VERSION 5.7 ;
BUSBITCHARS "[]" ;
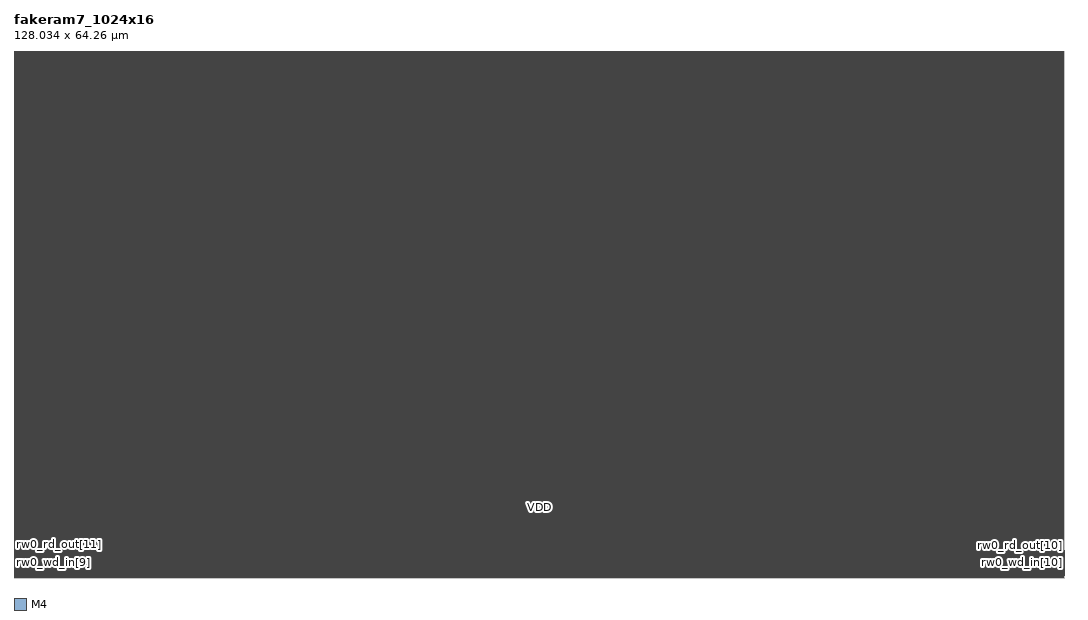
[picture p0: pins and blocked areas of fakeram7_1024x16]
MACRO fakeram7_1024x16
  FOREIGN fakeram7_1024x16 0 0 ;
  SYMMETRY X Y R90 ;
  SIZE 128.034 BY 64.260 ;
  CLASS BLOCK ;
  PIN rw0_clk
    DIRECTION INPUT ;
    USE SIGNAL ;
    SHAPE ABUTMENT ;
    PORT
      LAYER M4 ;
      RECT 0.000 0.276 0.072 0.300 ;
    END
  END rw0_clk
  PIN rw0_ce_in
    DIRECTION INPUT ;
    USE SIGNAL ;
    SHAPE ABUTMENT ;
    PORT
      LAYER M4 ;
      RECT 127.962 0.276 128.034 0.300 ;
    END
  END rw0_ce_in
  PIN rw0_we_in
    DIRECTION INPUT ;
    USE SIGNAL ;
    SHAPE ABUTMENT ;
    PORT
      LAYER M4 ;
      RECT 0.000 0.420 0.072 0.444 ;
    END
  END rw0_we_in
  PIN rw0_addr_in[0]
    DIRECTION INPUT ;
    USE SIGNAL ;
    SHAPE ABUTMENT ;
    PORT
      LAYER M4 ;
      RECT 127.962 0.420 128.034 0.444 ;
    END
  END rw0_addr_in[0]
  PIN rw0_addr_in[1]
    DIRECTION INPUT ;
    USE SIGNAL ;
    SHAPE ABUTMENT ;
    PORT
      LAYER M4 ;
      RECT 0.000 0.564 0.072 0.588 ;
    END
  END rw0_addr_in[1]
  PIN rw0_addr_in[2]
    DIRECTION INPUT ;
    USE SIGNAL ;
    SHAPE ABUTMENT ;
    PORT
      LAYER M4 ;
      RECT 127.962 0.564 128.034 0.588 ;
    END
  END rw0_addr_in[2]
  PIN rw0_addr_in[3]
    DIRECTION INPUT ;
    USE SIGNAL ;
    SHAPE ABUTMENT ;
    PORT
      LAYER M4 ;
      RECT 0.000 0.708 0.072 0.732 ;
    END
  END rw0_addr_in[3]
  PIN rw0_addr_in[4]
    DIRECTION INPUT ;
    USE SIGNAL ;
    SHAPE ABUTMENT ;
    PORT
      LAYER M4 ;
      RECT 127.962 0.708 128.034 0.732 ;
    END
  END rw0_addr_in[4]
  PIN rw0_addr_in[5]
    DIRECTION INPUT ;
    USE SIGNAL ;
    SHAPE ABUTMENT ;
    PORT
      LAYER M4 ;
      RECT 0.000 0.852 0.072 0.876 ;
    END
  END rw0_addr_in[5]
  PIN rw0_addr_in[6]
    DIRECTION INPUT ;
    USE SIGNAL ;
    SHAPE ABUTMENT ;
    PORT
      LAYER M4 ;
      RECT 127.962 0.852 128.034 0.876 ;
    END
  END rw0_addr_in[6]
  PIN rw0_addr_in[7]
    DIRECTION INPUT ;
    USE SIGNAL ;
    SHAPE ABUTMENT ;
    PORT
      LAYER M4 ;
      RECT 0.000 0.996 0.072 1.020 ;
    END
  END rw0_addr_in[7]
  PIN rw0_addr_in[8]
    DIRECTION INPUT ;
    USE SIGNAL ;
    SHAPE ABUTMENT ;
    PORT
      LAYER M4 ;
      RECT 127.962 0.996 128.034 1.020 ;
    END
  END rw0_addr_in[8]
  PIN rw0_addr_in[9]
    DIRECTION INPUT ;
    USE SIGNAL ;
    SHAPE ABUTMENT ;
    PORT
      LAYER M4 ;
      RECT 0.000 1.140 0.072 1.164 ;
    END
  END rw0_addr_in[9]
  PIN rw0_wd_in[0]
    DIRECTION INPUT ;
    USE SIGNAL ;
    SHAPE ABUTMENT ;
    PORT
      LAYER M4 ;
      RECT 127.962 1.140 128.034 1.164 ;
    END
  END rw0_wd_in[0]
  PIN rw0_wd_in[1]
    DIRECTION INPUT ;
    USE SIGNAL ;
    SHAPE ABUTMENT ;
    PORT
      LAYER M4 ;
      RECT 0.000 1.284 0.072 1.308 ;
    END
  END rw0_wd_in[1]
  PIN rw0_wd_in[2]
    DIRECTION INPUT ;
    USE SIGNAL ;
    SHAPE ABUTMENT ;
    PORT
      LAYER M4 ;
      RECT 127.962 1.284 128.034 1.308 ;
    END
  END rw0_wd_in[2]
  PIN rw0_wd_in[3]
    DIRECTION INPUT ;
    USE SIGNAL ;
    SHAPE ABUTMENT ;
    PORT
      LAYER M4 ;
      RECT 0.000 1.428 0.072 1.452 ;
    END
  END rw0_wd_in[3]
  PIN rw0_wd_in[4]
    DIRECTION INPUT ;
    USE SIGNAL ;
    SHAPE ABUTMENT ;
    PORT
      LAYER M4 ;
      RECT 127.962 1.428 128.034 1.452 ;
    END
  END rw0_wd_in[4]
  PIN rw0_wd_in[5]
    DIRECTION INPUT ;
    USE SIGNAL ;
    SHAPE ABUTMENT ;
    PORT
      LAYER M4 ;
      RECT 0.000 1.572 0.072 1.596 ;
    END
  END rw0_wd_in[5]
  PIN rw0_wd_in[6]
    DIRECTION INPUT ;
    USE SIGNAL ;
    SHAPE ABUTMENT ;
    PORT
      LAYER M4 ;
      RECT 127.962 1.572 128.034 1.596 ;
    END
  END rw0_wd_in[6]
  PIN rw0_wd_in[7]
    DIRECTION INPUT ;
    USE SIGNAL ;
    SHAPE ABUTMENT ;
    PORT
      LAYER M4 ;
      RECT 0.000 1.716 0.072 1.740 ;
    END
  END rw0_wd_in[7]
  PIN rw0_wd_in[8]
    DIRECTION INPUT ;
    USE SIGNAL ;
    SHAPE ABUTMENT ;
    PORT
      LAYER M4 ;
      RECT 127.962 1.716 128.034 1.740 ;
    END
  END rw0_wd_in[8]
  PIN rw0_wd_in[9]
    DIRECTION INPUT ;
    USE SIGNAL ;
    SHAPE ABUTMENT ;
    PORT
      LAYER M4 ;
      RECT 0.000 1.860 0.072 1.884 ;
    END
  END rw0_wd_in[9]
  PIN rw0_wd_in[10]
    DIRECTION INPUT ;
    USE SIGNAL ;
    SHAPE ABUTMENT ;
    PORT
      LAYER M4 ;
      RECT 127.962 1.860 128.034 1.884 ;
    END
  END rw0_wd_in[10]
  PIN rw0_wd_in[11]
    DIRECTION INPUT ;
    USE SIGNAL ;
    SHAPE ABUTMENT ;
    PORT
      LAYER M4 ;
      RECT 0.000 2.004 0.072 2.028 ;
    END
  END rw0_wd_in[11]
  PIN rw0_wd_in[12]
    DIRECTION INPUT ;
    USE SIGNAL ;
    SHAPE ABUTMENT ;
    PORT
      LAYER M4 ;
      RECT 127.962 2.004 128.034 2.028 ;
    END
  END rw0_wd_in[12]
  PIN rw0_wd_in[13]
    DIRECTION INPUT ;
    USE SIGNAL ;
    SHAPE ABUTMENT ;
    PORT
      LAYER M4 ;
      RECT 0.000 2.148 0.072 2.172 ;
    END
  END rw0_wd_in[13]
  PIN rw0_wd_in[14]
    DIRECTION INPUT ;
    USE SIGNAL ;
    SHAPE ABUTMENT ;
    PORT
      LAYER M4 ;
      RECT 127.962 2.148 128.034 2.172 ;
    END
  END rw0_wd_in[14]
  PIN rw0_wd_in[15]
    DIRECTION INPUT ;
    USE SIGNAL ;
    SHAPE ABUTMENT ;
    PORT
      LAYER M4 ;
      RECT 0.000 2.292 0.072 2.316 ;
    END
  END rw0_wd_in[15]
  PIN rw0_rd_out[0]
    DIRECTION OUTPUT ;
    USE SIGNAL ;
    SHAPE ABUTMENT ;
    PORT
      LAYER M4 ;
      RECT 127.962 2.292 128.034 2.316 ;
    END
  END rw0_rd_out[0]
  PIN rw0_rd_out[1]
    DIRECTION OUTPUT ;
    USE SIGNAL ;
    SHAPE ABUTMENT ;
    PORT
      LAYER M4 ;
      RECT 0.000 2.436 0.072 2.460 ;
    END
  END rw0_rd_out[1]
  PIN rw0_rd_out[2]
    DIRECTION OUTPUT ;
    USE SIGNAL ;
    SHAPE ABUTMENT ;
    PORT
      LAYER M4 ;
      RECT 127.962 2.436 128.034 2.460 ;
    END
  END rw0_rd_out[2]
  PIN rw0_rd_out[3]
    DIRECTION OUTPUT ;
    USE SIGNAL ;
    SHAPE ABUTMENT ;
    PORT
      LAYER M4 ;
      RECT 0.000 2.580 0.072 2.604 ;
    END
  END rw0_rd_out[3]
  PIN rw0_rd_out[4]
    DIRECTION OUTPUT ;
    USE SIGNAL ;
    SHAPE ABUTMENT ;
    PORT
      LAYER M4 ;
      RECT 127.962 2.580 128.034 2.604 ;
    END
  END rw0_rd_out[4]
  PIN rw0_rd_out[5]
    DIRECTION OUTPUT ;
    USE SIGNAL ;
    SHAPE ABUTMENT ;
    PORT
      LAYER M4 ;
      RECT 0.000 2.724 0.072 2.748 ;
    END
  END rw0_rd_out[5]
  PIN rw0_rd_out[6]
    DIRECTION OUTPUT ;
    USE SIGNAL ;
    SHAPE ABUTMENT ;
    PORT
      LAYER M4 ;
      RECT 127.962 2.724 128.034 2.748 ;
    END
  END rw0_rd_out[6]
  PIN rw0_rd_out[7]
    DIRECTION OUTPUT ;
    USE SIGNAL ;
    SHAPE ABUTMENT ;
    PORT
      LAYER M4 ;
      RECT 0.000 2.868 0.072 2.892 ;
    END
  END rw0_rd_out[7]
  PIN rw0_rd_out[8]
    DIRECTION OUTPUT ;
    USE SIGNAL ;
    SHAPE ABUTMENT ;
    PORT
      LAYER M4 ;
      RECT 127.962 2.868 128.034 2.892 ;
    END
  END rw0_rd_out[8]
  PIN rw0_rd_out[9]
    DIRECTION OUTPUT ;
    USE SIGNAL ;
    SHAPE ABUTMENT ;
    PORT
      LAYER M4 ;
      RECT 0.000 3.012 0.072 3.036 ;
    END
  END rw0_rd_out[9]
  PIN rw0_rd_out[10]
    DIRECTION OUTPUT ;
    USE SIGNAL ;
    SHAPE ABUTMENT ;
    PORT
      LAYER M4 ;
      RECT 127.962 3.012 128.034 3.036 ;
    END
  END rw0_rd_out[10]
  PIN rw0_rd_out[11]
    DIRECTION OUTPUT ;
    USE SIGNAL ;
    SHAPE ABUTMENT ;
    PORT
      LAYER M4 ;
      RECT 0.000 3.156 0.072 3.180 ;
    END
  END rw0_rd_out[11]
  PIN rw0_rd_out[12]
    DIRECTION OUTPUT ;
    USE SIGNAL ;
    SHAPE ABUTMENT ;
    PORT
      LAYER M4 ;
      RECT 127.962 3.156 128.034 3.180 ;
    END
  END rw0_rd_out[12]
  PIN rw0_rd_out[13]
    DIRECTION OUTPUT ;
    USE SIGNAL ;
    SHAPE ABUTMENT ;
    PORT
      LAYER M4 ;
      RECT 0.000 3.300 0.072 3.324 ;
    END
  END rw0_rd_out[13]
  PIN rw0_rd_out[14]
    DIRECTION OUTPUT ;
    USE SIGNAL ;
    SHAPE ABUTMENT ;
    PORT
      LAYER M4 ;
      RECT 127.962 3.300 128.034 3.324 ;
    END
  END rw0_rd_out[14]
  PIN rw0_rd_out[15]
    DIRECTION OUTPUT ;
    USE SIGNAL ;
    SHAPE ABUTMENT ;
    PORT
      LAYER M4 ;
      RECT 0.000 3.444 0.072 3.468 ;
    END
  END rw0_rd_out[15]
  PIN VDD
    DIRECTION INOUT ;
    USE POWER ;
    PORT
      LAYER M4 ;
      RECT 0.054 0.012 127.980 0.036 ;
      RECT 0.054 0.108 127.980 0.132 ;
      RECT 0.054 0.204 127.980 0.228 ;
      RECT 0.054 0.300 127.980 0.324 ;
      RECT 0.054 0.396 127.980 0.420 ;
      RECT 0.054 0.492 127.980 0.516 ;
      RECT 0.054 0.588 127.980 0.612 ;
      RECT 0.054 0.684 127.980 0.708 ;
      RECT 0.054 0.780 127.980 0.804 ;
      RECT 0.054 0.876 127.980 0.900 ;
      RECT 0.054 0.972 127.980 0.996 ;
      RECT 0.054 1.068 127.980 1.092 ;
      RECT 0.054 1.164 127.980 1.188 ;
      RECT 0.054 1.260 127.980 1.284 ;
      RECT 0.054 1.356 127.980 1.380 ;
      RECT 0.054 1.452 127.980 1.476 ;
      RECT 0.054 1.548 127.980 1.572 ;
      RECT 0.054 1.644 127.980 1.668 ;
      RECT 0.054 1.740 127.980 1.764 ;
      RECT 0.054 1.836 127.980 1.860 ;
      RECT 0.054 1.932 127.980 1.956 ;
      RECT 0.054 2.028 127.980 2.052 ;
      RECT 0.054 2.124 127.980 2.148 ;
      RECT 0.054 2.220 127.980 2.244 ;
      RECT 0.054 2.316 127.980 2.340 ;
      RECT 0.054 2.412 127.980 2.436 ;
      RECT 0.054 2.508 127.980 2.532 ;
      RECT 0.054 2.604 127.980 2.628 ;
      RECT 0.054 2.700 127.980 2.724 ;
      RECT 0.054 2.796 127.980 2.820 ;
      RECT 0.054 2.892 127.980 2.916 ;
      RECT 0.054 2.988 127.980 3.012 ;
      RECT 0.054 3.084 127.980 3.108 ;
      RECT 0.054 3.180 127.980 3.204 ;
      RECT 0.054 3.276 127.980 3.300 ;
      RECT 0.054 3.372 127.980 3.396 ;
      RECT 0.054 3.468 127.980 3.492 ;
      RECT 0.054 3.564 127.980 3.588 ;
      RECT 0.054 3.660 127.980 3.684 ;
      RECT 0.054 3.756 127.980 3.780 ;
      RECT 0.054 3.852 127.980 3.876 ;
      RECT 0.054 3.948 127.980 3.972 ;
      RECT 0.054 4.044 127.980 4.068 ;
      RECT 0.054 4.140 127.980 4.164 ;
      RECT 0.054 4.236 127.980 4.260 ;
      RECT 0.054 4.332 127.980 4.356 ;
      RECT 0.054 4.428 127.980 4.452 ;
      RECT 0.054 4.524 127.980 4.548 ;
      RECT 0.054 4.620 127.980 4.644 ;
      RECT 0.054 4.716 127.980 4.740 ;
      RECT 0.054 4.812 127.980 4.836 ;
      RECT 0.054 4.908 127.980 4.932 ;
      RECT 0.054 5.004 127.980 5.028 ;
      RECT 0.054 5.100 127.980 5.124 ;
      RECT 0.054 5.196 127.980 5.220 ;
      RECT 0.054 5.292 127.980 5.316 ;
      RECT 0.054 5.388 127.980 5.412 ;
      RECT 0.054 5.484 127.980 5.508 ;
      RECT 0.054 5.580 127.980 5.604 ;
      RECT 0.054 5.676 127.980 5.700 ;
      RECT 0.054 5.772 127.980 5.796 ;
      RECT 0.054 5.868 127.980 5.892 ;
      RECT 0.054 5.964 127.980 5.988 ;
      RECT 0.054 6.060 127.980 6.084 ;
      RECT 0.054 6.156 127.980 6.180 ;
      RECT 0.054 6.252 127.980 6.276 ;
      RECT 0.054 6.348 127.980 6.372 ;
      RECT 0.054 6.444 127.980 6.468 ;
      RECT 0.054 6.540 127.980 6.564 ;
      RECT 0.054 6.636 127.980 6.660 ;
      RECT 0.054 6.732 127.980 6.756 ;
      RECT 0.054 6.828 127.980 6.852 ;
      RECT 0.054 6.924 127.980 6.948 ;
      RECT 0.054 7.020 127.980 7.044 ;
      RECT 0.054 7.116 127.980 7.140 ;
      RECT 0.054 7.212 127.980 7.236 ;
      RECT 0.054 7.308 127.980 7.332 ;
      RECT 0.054 7.404 127.980 7.428 ;
      RECT 0.054 7.500 127.980 7.524 ;
      RECT 0.054 7.596 127.980 7.620 ;
      RECT 0.054 7.692 127.980 7.716 ;
      RECT 0.054 7.788 127.980 7.812 ;
      RECT 0.054 7.884 127.980 7.908 ;
      RECT 0.054 7.980 127.980 8.004 ;
      RECT 0.054 8.076 127.980 8.100 ;
      RECT 0.054 8.172 127.980 8.196 ;
      RECT 0.054 8.268 127.980 8.292 ;
      RECT 0.054 8.364 127.980 8.388 ;
      RECT 0.054 8.460 127.980 8.484 ;
      RECT 0.054 8.556 127.980 8.580 ;
      RECT 0.054 8.652 127.980 8.676 ;
      RECT 0.054 8.748 127.980 8.772 ;
      RECT 0.054 8.844 127.980 8.868 ;
      RECT 0.054 8.940 127.980 8.964 ;
      RECT 0.054 9.036 127.980 9.060 ;
      RECT 0.054 9.132 127.980 9.156 ;
      RECT 0.054 9.228 127.980 9.252 ;
      RECT 0.054 9.324 127.980 9.348 ;
      RECT 0.054 9.420 127.980 9.444 ;
      RECT 0.054 9.516 127.980 9.540 ;
      RECT 0.054 9.612 127.980 9.636 ;
      RECT 0.054 9.708 127.980 9.732 ;
      RECT 0.054 9.804 127.980 9.828 ;
      RECT 0.054 9.900 127.980 9.924 ;
      RECT 0.054 9.996 127.980 10.020 ;
      RECT 0.054 10.092 127.980 10.116 ;
      RECT 0.054 10.188 127.980 10.212 ;
      RECT 0.054 10.284 127.980 10.308 ;
      RECT 0.054 10.380 127.980 10.404 ;
      RECT 0.054 10.476 127.980 10.500 ;
      RECT 0.054 10.572 127.980 10.596 ;
      RECT 0.054 10.668 127.980 10.692 ;
      RECT 0.054 10.764 127.980 10.788 ;
      RECT 0.054 10.860 127.980 10.884 ;
      RECT 0.054 10.956 127.980 10.980 ;
      RECT 0.054 11.052 127.980 11.076 ;
      RECT 0.054 11.148 127.980 11.172 ;
      RECT 0.054 11.244 127.980 11.268 ;
      RECT 0.054 11.340 127.980 11.364 ;
      RECT 0.054 11.436 127.980 11.460 ;
      RECT 0.054 11.532 127.980 11.556 ;
      RECT 0.054 11.628 127.980 11.652 ;
      RECT 0.054 11.724 127.980 11.748 ;
      RECT 0.054 11.820 127.980 11.844 ;
      RECT 0.054 11.916 127.980 11.940 ;
      RECT 0.054 12.012 127.980 12.036 ;
      RECT 0.054 12.108 127.980 12.132 ;
      RECT 0.054 12.204 127.980 12.228 ;
      RECT 0.054 12.300 127.980 12.324 ;
      RECT 0.054 12.396 127.980 12.420 ;
      RECT 0.054 12.492 127.980 12.516 ;
      RECT 0.054 12.588 127.980 12.612 ;
      RECT 0.054 12.684 127.980 12.708 ;
      RECT 0.054 12.780 127.980 12.804 ;
      RECT 0.054 12.876 127.980 12.900 ;
      RECT 0.054 12.972 127.980 12.996 ;
      RECT 0.054 13.068 127.980 13.092 ;
      RECT 0.054 13.164 127.980 13.188 ;
      RECT 0.054 13.260 127.980 13.284 ;
      RECT 0.054 13.356 127.980 13.380 ;
      RECT 0.054 13.452 127.980 13.476 ;
      RECT 0.054 13.548 127.980 13.572 ;
      RECT 0.054 13.644 127.980 13.668 ;
      RECT 0.054 13.740 127.980 13.764 ;
      RECT 0.054 13.836 127.980 13.860 ;
      RECT 0.054 13.932 127.980 13.956 ;
      RECT 0.054 14.028 127.980 14.052 ;
      RECT 0.054 14.124 127.980 14.148 ;
      RECT 0.054 14.220 127.980 14.244 ;
      RECT 0.054 14.316 127.980 14.340 ;
      RECT 0.054 14.412 127.980 14.436 ;
      RECT 0.054 14.508 127.980 14.532 ;
      RECT 0.054 14.604 127.980 14.628 ;
      RECT 0.054 14.700 127.980 14.724 ;
      RECT 0.054 14.796 127.980 14.820 ;
      RECT 0.054 14.892 127.980 14.916 ;
      RECT 0.054 14.988 127.980 15.012 ;
      RECT 0.054 15.084 127.980 15.108 ;
      RECT 0.054 15.180 127.980 15.204 ;
      RECT 0.054 15.276 127.980 15.300 ;
      RECT 0.054 15.372 127.980 15.396 ;
      RECT 0.054 15.468 127.980 15.492 ;
      RECT 0.054 15.564 127.980 15.588 ;
      RECT 0.054 15.660 127.980 15.684 ;
      RECT 0.054 15.756 127.980 15.780 ;
      RECT 0.054 15.852 127.980 15.876 ;
      RECT 0.054 15.948 127.980 15.972 ;
      RECT 0.054 16.044 127.980 16.068 ;
      RECT 0.054 16.140 127.980 16.164 ;
      RECT 0.054 16.236 127.980 16.260 ;
      RECT 0.054 16.332 127.980 16.356 ;
      RECT 0.054 16.428 127.980 16.452 ;
      RECT 0.054 16.524 127.980 16.548 ;
      RECT 0.054 16.620 127.980 16.644 ;
      RECT 0.054 16.716 127.980 16.740 ;
      RECT 0.054 16.812 127.980 16.836 ;
      RECT 0.054 16.908 127.980 16.932 ;
      RECT 0.054 17.004 127.980 17.028 ;
      RECT 0.054 17.100 127.980 17.124 ;
      RECT 0.054 17.196 127.980 17.220 ;
      RECT 0.054 17.292 127.980 17.316 ;
      RECT 0.054 17.388 127.980 17.412 ;
      RECT 0.054 17.484 127.980 17.508 ;
      RECT 0.054 17.580 127.980 17.604 ;
      RECT 0.054 17.676 127.980 17.700 ;
      RECT 0.054 17.772 127.980 17.796 ;
      RECT 0.054 17.868 127.980 17.892 ;
      RECT 0.054 17.964 127.980 17.988 ;
      RECT 0.054 18.060 127.980 18.084 ;
      RECT 0.054 18.156 127.980 18.180 ;
      RECT 0.054 18.252 127.980 18.276 ;
      RECT 0.054 18.348 127.980 18.372 ;
      RECT 0.054 18.444 127.980 18.468 ;
      RECT 0.054 18.540 127.980 18.564 ;
      RECT 0.054 18.636 127.980 18.660 ;
      RECT 0.054 18.732 127.980 18.756 ;
      RECT 0.054 18.828 127.980 18.852 ;
      RECT 0.054 18.924 127.980 18.948 ;
      RECT 0.054 19.020 127.980 19.044 ;
      RECT 0.054 19.116 127.980 19.140 ;
      RECT 0.054 19.212 127.980 19.236 ;
      RECT 0.054 19.308 127.980 19.332 ;
      RECT 0.054 19.404 127.980 19.428 ;
      RECT 0.054 19.500 127.980 19.524 ;
      RECT 0.054 19.596 127.980 19.620 ;
      RECT 0.054 19.692 127.980 19.716 ;
      RECT 0.054 19.788 127.980 19.812 ;
      RECT 0.054 19.884 127.980 19.908 ;
      RECT 0.054 19.980 127.980 20.004 ;
      RECT 0.054 20.076 127.980 20.100 ;
      RECT 0.054 20.172 127.980 20.196 ;
      RECT 0.054 20.268 127.980 20.292 ;
      RECT 0.054 20.364 127.980 20.388 ;
      RECT 0.054 20.460 127.980 20.484 ;
      RECT 0.054 20.556 127.980 20.580 ;
      RECT 0.054 20.652 127.980 20.676 ;
      RECT 0.054 20.748 127.980 20.772 ;
      RECT 0.054 20.844 127.980 20.868 ;
      RECT 0.054 20.940 127.980 20.964 ;
      RECT 0.054 21.036 127.980 21.060 ;
      RECT 0.054 21.132 127.980 21.156 ;
      RECT 0.054 21.228 127.980 21.252 ;
      RECT 0.054 21.324 127.980 21.348 ;
      RECT 0.054 21.420 127.980 21.444 ;
      RECT 0.054 21.516 127.980 21.540 ;
      RECT 0.054 21.612 127.980 21.636 ;
      RECT 0.054 21.708 127.980 21.732 ;
      RECT 0.054 21.804 127.980 21.828 ;
      RECT 0.054 21.900 127.980 21.924 ;
      RECT 0.054 21.996 127.980 22.020 ;
      RECT 0.054 22.092 127.980 22.116 ;
      RECT 0.054 22.188 127.980 22.212 ;
      RECT 0.054 22.284 127.980 22.308 ;
      RECT 0.054 22.380 127.980 22.404 ;
      RECT 0.054 22.476 127.980 22.500 ;
      RECT 0.054 22.572 127.980 22.596 ;
      RECT 0.054 22.668 127.980 22.692 ;
      RECT 0.054 22.764 127.980 22.788 ;
      RECT 0.054 22.860 127.980 22.884 ;
      RECT 0.054 22.956 127.980 22.980 ;
      RECT 0.054 23.052 127.980 23.076 ;
      RECT 0.054 23.148 127.980 23.172 ;
      RECT 0.054 23.244 127.980 23.268 ;
      RECT 0.054 23.340 127.980 23.364 ;
      RECT 0.054 23.436 127.980 23.460 ;
      RECT 0.054 23.532 127.980 23.556 ;
      RECT 0.054 23.628 127.980 23.652 ;
      RECT 0.054 23.724 127.980 23.748 ;
      RECT 0.054 23.820 127.980 23.844 ;
      RECT 0.054 23.916 127.980 23.940 ;
      RECT 0.054 24.012 127.980 24.036 ;
      RECT 0.054 24.108 127.980 24.132 ;
      RECT 0.054 24.204 127.980 24.228 ;
      RECT 0.054 24.300 127.980 24.324 ;
      RECT 0.054 24.396 127.980 24.420 ;
      RECT 0.054 24.492 127.980 24.516 ;
      RECT 0.054 24.588 127.980 24.612 ;
      RECT 0.054 24.684 127.980 24.708 ;
      RECT 0.054 24.780 127.980 24.804 ;
      RECT 0.054 24.876 127.980 24.900 ;
      RECT 0.054 24.972 127.980 24.996 ;
      RECT 0.054 25.068 127.980 25.092 ;
      RECT 0.054 25.164 127.980 25.188 ;
      RECT 0.054 25.260 127.980 25.284 ;
      RECT 0.054 25.356 127.980 25.380 ;
      RECT 0.054 25.452 127.980 25.476 ;
      RECT 0.054 25.548 127.980 25.572 ;
      RECT 0.054 25.644 127.980 25.668 ;
      RECT 0.054 25.740 127.980 25.764 ;
      RECT 0.054 25.836 127.980 25.860 ;
      RECT 0.054 25.932 127.980 25.956 ;
      RECT 0.054 26.028 127.980 26.052 ;
      RECT 0.054 26.124 127.980 26.148 ;
      RECT 0.054 26.220 127.980 26.244 ;
      RECT 0.054 26.316 127.980 26.340 ;
      RECT 0.054 26.412 127.980 26.436 ;
      RECT 0.054 26.508 127.980 26.532 ;
      RECT 0.054 26.604 127.980 26.628 ;
      RECT 0.054 26.700 127.980 26.724 ;
      RECT 0.054 26.796 127.980 26.820 ;
      RECT 0.054 26.892 127.980 26.916 ;
      RECT 0.054 26.988 127.980 27.012 ;
      RECT 0.054 27.084 127.980 27.108 ;
      RECT 0.054 27.180 127.980 27.204 ;
      RECT 0.054 27.276 127.980 27.300 ;
      RECT 0.054 27.372 127.980 27.396 ;
      RECT 0.054 27.468 127.980 27.492 ;
      RECT 0.054 27.564 127.980 27.588 ;
      RECT 0.054 27.660 127.980 27.684 ;
      RECT 0.054 27.756 127.980 27.780 ;
      RECT 0.054 27.852 127.980 27.876 ;
      RECT 0.054 27.948 127.980 27.972 ;
      RECT 0.054 28.044 127.980 28.068 ;
      RECT 0.054 28.140 127.980 28.164 ;
      RECT 0.054 28.236 127.980 28.260 ;
      RECT 0.054 28.332 127.980 28.356 ;
      RECT 0.054 28.428 127.980 28.452 ;
      RECT 0.054 28.524 127.980 28.548 ;
      RECT 0.054 28.620 127.980 28.644 ;
      RECT 0.054 28.716 127.980 28.740 ;
      RECT 0.054 28.812 127.980 28.836 ;
      RECT 0.054 28.908 127.980 28.932 ;
      RECT 0.054 29.004 127.980 29.028 ;
      RECT 0.054 29.100 127.980 29.124 ;
      RECT 0.054 29.196 127.980 29.220 ;
      RECT 0.054 29.292 127.980 29.316 ;
      RECT 0.054 29.388 127.980 29.412 ;
      RECT 0.054 29.484 127.980 29.508 ;
      RECT 0.054 29.580 127.980 29.604 ;
      RECT 0.054 29.676 127.980 29.700 ;
      RECT 0.054 29.772 127.980 29.796 ;
      RECT 0.054 29.868 127.980 29.892 ;
      RECT 0.054 29.964 127.980 29.988 ;
      RECT 0.054 30.060 127.980 30.084 ;
      RECT 0.054 30.156 127.980 30.180 ;
      RECT 0.054 30.252 127.980 30.276 ;
      RECT 0.054 30.348 127.980 30.372 ;
      RECT 0.054 30.444 127.980 30.468 ;
      RECT 0.054 30.540 127.980 30.564 ;
      RECT 0.054 30.636 127.980 30.660 ;
      RECT 0.054 30.732 127.980 30.756 ;
      RECT 0.054 30.828 127.980 30.852 ;
      RECT 0.054 30.924 127.980 30.948 ;
      RECT 0.054 31.020 127.980 31.044 ;
      RECT 0.054 31.116 127.980 31.140 ;
      RECT 0.054 31.212 127.980 31.236 ;
      RECT 0.054 31.308 127.980 31.332 ;
      RECT 0.054 31.404 127.980 31.428 ;
      RECT 0.054 31.500 127.980 31.524 ;
      RECT 0.054 31.596 127.980 31.620 ;
      RECT 0.054 31.692 127.980 31.716 ;
      RECT 0.054 31.788 127.980 31.812 ;
      RECT 0.054 31.884 127.980 31.908 ;
      RECT 0.054 31.980 127.980 32.004 ;
      RECT 0.054 32.076 127.980 32.100 ;
      RECT 0.054 32.172 127.980 32.196 ;
      RECT 0.054 32.268 127.980 32.292 ;
      RECT 0.054 32.364 127.980 32.388 ;
      RECT 0.054 32.460 127.980 32.484 ;
      RECT 0.054 32.556 127.980 32.580 ;
      RECT 0.054 32.652 127.980 32.676 ;
      RECT 0.054 32.748 127.980 32.772 ;
      RECT 0.054 32.844 127.980 32.868 ;
      RECT 0.054 32.940 127.980 32.964 ;
      RECT 0.054 33.036 127.980 33.060 ;
      RECT 0.054 33.132 127.980 33.156 ;
      RECT 0.054 33.228 127.980 33.252 ;
      RECT 0.054 33.324 127.980 33.348 ;
      RECT 0.054 33.420 127.980 33.444 ;
      RECT 0.054 33.516 127.980 33.540 ;
      RECT 0.054 33.612 127.980 33.636 ;
      RECT 0.054 33.708 127.980 33.732 ;
      RECT 0.054 33.804 127.980 33.828 ;
      RECT 0.054 33.900 127.980 33.924 ;
      RECT 0.054 33.996 127.980 34.020 ;
      RECT 0.054 34.092 127.980 34.116 ;
      RECT 0.054 34.188 127.980 34.212 ;
      RECT 0.054 34.284 127.980 34.308 ;
      RECT 0.054 34.380 127.980 34.404 ;
      RECT 0.054 34.476 127.980 34.500 ;
      RECT 0.054 34.572 127.980 34.596 ;
      RECT 0.054 34.668 127.980 34.692 ;
      RECT 0.054 34.764 127.980 34.788 ;
      RECT 0.054 34.860 127.980 34.884 ;
      RECT 0.054 34.956 127.980 34.980 ;
      RECT 0.054 35.052 127.980 35.076 ;
      RECT 0.054 35.148 127.980 35.172 ;
      RECT 0.054 35.244 127.980 35.268 ;
      RECT 0.054 35.340 127.980 35.364 ;
      RECT 0.054 35.436 127.980 35.460 ;
      RECT 0.054 35.532 127.980 35.556 ;
      RECT 0.054 35.628 127.980 35.652 ;
      RECT 0.054 35.724 127.980 35.748 ;
      RECT 0.054 35.820 127.980 35.844 ;
      RECT 0.054 35.916 127.980 35.940 ;
      RECT 0.054 36.012 127.980 36.036 ;
      RECT 0.054 36.108 127.980 36.132 ;
      RECT 0.054 36.204 127.980 36.228 ;
      RECT 0.054 36.300 127.980 36.324 ;
      RECT 0.054 36.396 127.980 36.420 ;
      RECT 0.054 36.492 127.980 36.516 ;
      RECT 0.054 36.588 127.980 36.612 ;
      RECT 0.054 36.684 127.980 36.708 ;
      RECT 0.054 36.780 127.980 36.804 ;
      RECT 0.054 36.876 127.980 36.900 ;
      RECT 0.054 36.972 127.980 36.996 ;
      RECT 0.054 37.068 127.980 37.092 ;
      RECT 0.054 37.164 127.980 37.188 ;
      RECT 0.054 37.260 127.980 37.284 ;
      RECT 0.054 37.356 127.980 37.380 ;
      RECT 0.054 37.452 127.980 37.476 ;
      RECT 0.054 37.548 127.980 37.572 ;
      RECT 0.054 37.644 127.980 37.668 ;
      RECT 0.054 37.740 127.980 37.764 ;
      RECT 0.054 37.836 127.980 37.860 ;
      RECT 0.054 37.932 127.980 37.956 ;
      RECT 0.054 38.028 127.980 38.052 ;
      RECT 0.054 38.124 127.980 38.148 ;
      RECT 0.054 38.220 127.980 38.244 ;
      RECT 0.054 38.316 127.980 38.340 ;
      RECT 0.054 38.412 127.980 38.436 ;
      RECT 0.054 38.508 127.980 38.532 ;
      RECT 0.054 38.604 127.980 38.628 ;
      RECT 0.054 38.700 127.980 38.724 ;
      RECT 0.054 38.796 127.980 38.820 ;
      RECT 0.054 38.892 127.980 38.916 ;
      RECT 0.054 38.988 127.980 39.012 ;
      RECT 0.054 39.084 127.980 39.108 ;
      RECT 0.054 39.180 127.980 39.204 ;
      RECT 0.054 39.276 127.980 39.300 ;
      RECT 0.054 39.372 127.980 39.396 ;
      RECT 0.054 39.468 127.980 39.492 ;
      RECT 0.054 39.564 127.980 39.588 ;
      RECT 0.054 39.660 127.980 39.684 ;
      RECT 0.054 39.756 127.980 39.780 ;
      RECT 0.054 39.852 127.980 39.876 ;
      RECT 0.054 39.948 127.980 39.972 ;
      RECT 0.054 40.044 127.980 40.068 ;
      RECT 0.054 40.140 127.980 40.164 ;
      RECT 0.054 40.236 127.980 40.260 ;
      RECT 0.054 40.332 127.980 40.356 ;
      RECT 0.054 40.428 127.980 40.452 ;
      RECT 0.054 40.524 127.980 40.548 ;
      RECT 0.054 40.620 127.980 40.644 ;
      RECT 0.054 40.716 127.980 40.740 ;
      RECT 0.054 40.812 127.980 40.836 ;
      RECT 0.054 40.908 127.980 40.932 ;
      RECT 0.054 41.004 127.980 41.028 ;
      RECT 0.054 41.100 127.980 41.124 ;
      RECT 0.054 41.196 127.980 41.220 ;
      RECT 0.054 41.292 127.980 41.316 ;
      RECT 0.054 41.388 127.980 41.412 ;
      RECT 0.054 41.484 127.980 41.508 ;
      RECT 0.054 41.580 127.980 41.604 ;
      RECT 0.054 41.676 127.980 41.700 ;
      RECT 0.054 41.772 127.980 41.796 ;
      RECT 0.054 41.868 127.980 41.892 ;
      RECT 0.054 41.964 127.980 41.988 ;
      RECT 0.054 42.060 127.980 42.084 ;
      RECT 0.054 42.156 127.980 42.180 ;
      RECT 0.054 42.252 127.980 42.276 ;
      RECT 0.054 42.348 127.980 42.372 ;
      RECT 0.054 42.444 127.980 42.468 ;
      RECT 0.054 42.540 127.980 42.564 ;
      RECT 0.054 42.636 127.980 42.660 ;
      RECT 0.054 42.732 127.980 42.756 ;
      RECT 0.054 42.828 127.980 42.852 ;
      RECT 0.054 42.924 127.980 42.948 ;
      RECT 0.054 43.020 127.980 43.044 ;
      RECT 0.054 43.116 127.980 43.140 ;
      RECT 0.054 43.212 127.980 43.236 ;
      RECT 0.054 43.308 127.980 43.332 ;
      RECT 0.054 43.404 127.980 43.428 ;
      RECT 0.054 43.500 127.980 43.524 ;
      RECT 0.054 43.596 127.980 43.620 ;
      RECT 0.054 43.692 127.980 43.716 ;
      RECT 0.054 43.788 127.980 43.812 ;
      RECT 0.054 43.884 127.980 43.908 ;
      RECT 0.054 43.980 127.980 44.004 ;
      RECT 0.054 44.076 127.980 44.100 ;
      RECT 0.054 44.172 127.980 44.196 ;
      RECT 0.054 44.268 127.980 44.292 ;
      RECT 0.054 44.364 127.980 44.388 ;
      RECT 0.054 44.460 127.980 44.484 ;
      RECT 0.054 44.556 127.980 44.580 ;
      RECT 0.054 44.652 127.980 44.676 ;
      RECT 0.054 44.748 127.980 44.772 ;
      RECT 0.054 44.844 127.980 44.868 ;
      RECT 0.054 44.940 127.980 44.964 ;
      RECT 0.054 45.036 127.980 45.060 ;
      RECT 0.054 45.132 127.980 45.156 ;
      RECT 0.054 45.228 127.980 45.252 ;
      RECT 0.054 45.324 127.980 45.348 ;
      RECT 0.054 45.420 127.980 45.444 ;
      RECT 0.054 45.516 127.980 45.540 ;
      RECT 0.054 45.612 127.980 45.636 ;
      RECT 0.054 45.708 127.980 45.732 ;
      RECT 0.054 45.804 127.980 45.828 ;
      RECT 0.054 45.900 127.980 45.924 ;
      RECT 0.054 45.996 127.980 46.020 ;
      RECT 0.054 46.092 127.980 46.116 ;
      RECT 0.054 46.188 127.980 46.212 ;
      RECT 0.054 46.284 127.980 46.308 ;
      RECT 0.054 46.380 127.980 46.404 ;
      RECT 0.054 46.476 127.980 46.500 ;
      RECT 0.054 46.572 127.980 46.596 ;
      RECT 0.054 46.668 127.980 46.692 ;
      RECT 0.054 46.764 127.980 46.788 ;
      RECT 0.054 46.860 127.980 46.884 ;
      RECT 0.054 46.956 127.980 46.980 ;
      RECT 0.054 47.052 127.980 47.076 ;
      RECT 0.054 47.148 127.980 47.172 ;
      RECT 0.054 47.244 127.980 47.268 ;
      RECT 0.054 47.340 127.980 47.364 ;
      RECT 0.054 47.436 127.980 47.460 ;
      RECT 0.054 47.532 127.980 47.556 ;
      RECT 0.054 47.628 127.980 47.652 ;
      RECT 0.054 47.724 127.980 47.748 ;
      RECT 0.054 47.820 127.980 47.844 ;
      RECT 0.054 47.916 127.980 47.940 ;
      RECT 0.054 48.012 127.980 48.036 ;
      RECT 0.054 48.108 127.980 48.132 ;
      RECT 0.054 48.204 127.980 48.228 ;
      RECT 0.054 48.300 127.980 48.324 ;
      RECT 0.054 48.396 127.980 48.420 ;
      RECT 0.054 48.492 127.980 48.516 ;
      RECT 0.054 48.588 127.980 48.612 ;
      RECT 0.054 48.684 127.980 48.708 ;
      RECT 0.054 48.780 127.980 48.804 ;
      RECT 0.054 48.876 127.980 48.900 ;
      RECT 0.054 48.972 127.980 48.996 ;
      RECT 0.054 49.068 127.980 49.092 ;
      RECT 0.054 49.164 127.980 49.188 ;
      RECT 0.054 49.260 127.980 49.284 ;
      RECT 0.054 49.356 127.980 49.380 ;
      RECT 0.054 49.452 127.980 49.476 ;
      RECT 0.054 49.548 127.980 49.572 ;
      RECT 0.054 49.644 127.980 49.668 ;
      RECT 0.054 49.740 127.980 49.764 ;
      RECT 0.054 49.836 127.980 49.860 ;
      RECT 0.054 49.932 127.980 49.956 ;
      RECT 0.054 50.028 127.980 50.052 ;
      RECT 0.054 50.124 127.980 50.148 ;
      RECT 0.054 50.220 127.980 50.244 ;
      RECT 0.054 50.316 127.980 50.340 ;
      RECT 0.054 50.412 127.980 50.436 ;
      RECT 0.054 50.508 127.980 50.532 ;
      RECT 0.054 50.604 127.980 50.628 ;
      RECT 0.054 50.700 127.980 50.724 ;
      RECT 0.054 50.796 127.980 50.820 ;
      RECT 0.054 50.892 127.980 50.916 ;
      RECT 0.054 50.988 127.980 51.012 ;
      RECT 0.054 51.084 127.980 51.108 ;
      RECT 0.054 51.180 127.980 51.204 ;
      RECT 0.054 51.276 127.980 51.300 ;
      RECT 0.054 51.372 127.980 51.396 ;
      RECT 0.054 51.468 127.980 51.492 ;
      RECT 0.054 51.564 127.980 51.588 ;
      RECT 0.054 51.660 127.980 51.684 ;
      RECT 0.054 51.756 127.980 51.780 ;
      RECT 0.054 51.852 127.980 51.876 ;
      RECT 0.054 51.948 127.980 51.972 ;
      RECT 0.054 52.044 127.980 52.068 ;
      RECT 0.054 52.140 127.980 52.164 ;
      RECT 0.054 52.236 127.980 52.260 ;
      RECT 0.054 52.332 127.980 52.356 ;
      RECT 0.054 52.428 127.980 52.452 ;
      RECT 0.054 52.524 127.980 52.548 ;
      RECT 0.054 52.620 127.980 52.644 ;
      RECT 0.054 52.716 127.980 52.740 ;
      RECT 0.054 52.812 127.980 52.836 ;
      RECT 0.054 52.908 127.980 52.932 ;
      RECT 0.054 53.004 127.980 53.028 ;
      RECT 0.054 53.100 127.980 53.124 ;
      RECT 0.054 53.196 127.980 53.220 ;
      RECT 0.054 53.292 127.980 53.316 ;
      RECT 0.054 53.388 127.980 53.412 ;
      RECT 0.054 53.484 127.980 53.508 ;
      RECT 0.054 53.580 127.980 53.604 ;
      RECT 0.054 53.676 127.980 53.700 ;
      RECT 0.054 53.772 127.980 53.796 ;
      RECT 0.054 53.868 127.980 53.892 ;
      RECT 0.054 53.964 127.980 53.988 ;
      RECT 0.054 54.060 127.980 54.084 ;
      RECT 0.054 54.156 127.980 54.180 ;
      RECT 0.054 54.252 127.980 54.276 ;
      RECT 0.054 54.348 127.980 54.372 ;
      RECT 0.054 54.444 127.980 54.468 ;
      RECT 0.054 54.540 127.980 54.564 ;
      RECT 0.054 54.636 127.980 54.660 ;
      RECT 0.054 54.732 127.980 54.756 ;
      RECT 0.054 54.828 127.980 54.852 ;
      RECT 0.054 54.924 127.980 54.948 ;
      RECT 0.054 55.020 127.980 55.044 ;
      RECT 0.054 55.116 127.980 55.140 ;
      RECT 0.054 55.212 127.980 55.236 ;
      RECT 0.054 55.308 127.980 55.332 ;
      RECT 0.054 55.404 127.980 55.428 ;
      RECT 0.054 55.500 127.980 55.524 ;
      RECT 0.054 55.596 127.980 55.620 ;
      RECT 0.054 55.692 127.980 55.716 ;
      RECT 0.054 55.788 127.980 55.812 ;
      RECT 0.054 55.884 127.980 55.908 ;
      RECT 0.054 55.980 127.980 56.004 ;
      RECT 0.054 56.076 127.980 56.100 ;
      RECT 0.054 56.172 127.980 56.196 ;
      RECT 0.054 56.268 127.980 56.292 ;
      RECT 0.054 56.364 127.980 56.388 ;
      RECT 0.054 56.460 127.980 56.484 ;
      RECT 0.054 56.556 127.980 56.580 ;
      RECT 0.054 56.652 127.980 56.676 ;
      RECT 0.054 56.748 127.980 56.772 ;
      RECT 0.054 56.844 127.980 56.868 ;
      RECT 0.054 56.940 127.980 56.964 ;
      RECT 0.054 57.036 127.980 57.060 ;
      RECT 0.054 57.132 127.980 57.156 ;
      RECT 0.054 57.228 127.980 57.252 ;
      RECT 0.054 57.324 127.980 57.348 ;
      RECT 0.054 57.420 127.980 57.444 ;
      RECT 0.054 57.516 127.980 57.540 ;
      RECT 0.054 57.612 127.980 57.636 ;
      RECT 0.054 57.708 127.980 57.732 ;
      RECT 0.054 57.804 127.980 57.828 ;
      RECT 0.054 57.900 127.980 57.924 ;
      RECT 0.054 57.996 127.980 58.020 ;
      RECT 0.054 58.092 127.980 58.116 ;
      RECT 0.054 58.188 127.980 58.212 ;
      RECT 0.054 58.284 127.980 58.308 ;
      RECT 0.054 58.380 127.980 58.404 ;
      RECT 0.054 58.476 127.980 58.500 ;
      RECT 0.054 58.572 127.980 58.596 ;
      RECT 0.054 58.668 127.980 58.692 ;
      RECT 0.054 58.764 127.980 58.788 ;
      RECT 0.054 58.860 127.980 58.884 ;
      RECT 0.054 58.956 127.980 58.980 ;
      RECT 0.054 59.052 127.980 59.076 ;
      RECT 0.054 59.148 127.980 59.172 ;
      RECT 0.054 59.244 127.980 59.268 ;
      RECT 0.054 59.340 127.980 59.364 ;
      RECT 0.054 59.436 127.980 59.460 ;
      RECT 0.054 59.532 127.980 59.556 ;
      RECT 0.054 59.628 127.980 59.652 ;
      RECT 0.054 59.724 127.980 59.748 ;
      RECT 0.054 59.820 127.980 59.844 ;
      RECT 0.054 59.916 127.980 59.940 ;
      RECT 0.054 60.012 127.980 60.036 ;
      RECT 0.054 60.108 127.980 60.132 ;
      RECT 0.054 60.204 127.980 60.228 ;
      RECT 0.054 60.300 127.980 60.324 ;
      RECT 0.054 60.396 127.980 60.420 ;
      RECT 0.054 60.492 127.980 60.516 ;
      RECT 0.054 60.588 127.980 60.612 ;
      RECT 0.054 60.684 127.980 60.708 ;
      RECT 0.054 60.780 127.980 60.804 ;
      RECT 0.054 60.876 127.980 60.900 ;
      RECT 0.054 60.972 127.980 60.996 ;
      RECT 0.054 61.068 127.980 61.092 ;
      RECT 0.054 61.164 127.980 61.188 ;
      RECT 0.054 61.260 127.980 61.284 ;
      RECT 0.054 61.356 127.980 61.380 ;
      RECT 0.054 61.452 127.980 61.476 ;
      RECT 0.054 61.548 127.980 61.572 ;
      RECT 0.054 61.644 127.980 61.668 ;
      RECT 0.054 61.740 127.980 61.764 ;
      RECT 0.054 61.836 127.980 61.860 ;
      RECT 0.054 61.932 127.980 61.956 ;
      RECT 0.054 62.028 127.980 62.052 ;
      RECT 0.054 62.124 127.980 62.148 ;
      RECT 0.054 62.220 127.980 62.244 ;
      RECT 0.054 62.316 127.980 62.340 ;
      RECT 0.054 62.412 127.980 62.436 ;
      RECT 0.054 62.508 127.980 62.532 ;
      RECT 0.054 62.604 127.980 62.628 ;
      RECT 0.054 62.700 127.980 62.724 ;
      RECT 0.054 62.796 127.980 62.820 ;
      RECT 0.054 62.892 127.980 62.916 ;
      RECT 0.054 62.988 127.980 63.012 ;
      RECT 0.054 63.084 127.980 63.108 ;
      RECT 0.054 63.180 127.980 63.204 ;
      RECT 0.054 63.276 127.980 63.300 ;
      RECT 0.054 63.372 127.980 63.396 ;
      RECT 0.054 63.468 127.980 63.492 ;
      RECT 0.054 63.564 127.980 63.588 ;
      RECT 0.054 63.660 127.980 63.684 ;
      RECT 0.054 63.756 127.980 63.780 ;
      RECT 0.054 63.852 127.980 63.876 ;
      RECT 0.054 63.948 127.980 63.972 ;
      RECT 0.054 64.044 127.980 64.068 ;
      RECT 0.054 64.140 127.980 64.164 ;
      RECT 0.054 64.236 127.980 64.260 ;
    END
  END VDD
  PIN VSS
    DIRECTION INOUT ;
    USE GROUND ;
    PORT
      LAYER M4 ;
      RECT 0.054 0.060 127.980 0.084 ;
      RECT 0.054 0.156 127.980 0.180 ;
      RECT 0.054 0.252 127.980 0.276 ;
      RECT 0.054 0.348 127.980 0.372 ;
      RECT 0.054 0.444 127.980 0.468 ;
      RECT 0.054 0.540 127.980 0.564 ;
      RECT 0.054 0.636 127.980 0.660 ;
      RECT 0.054 0.732 127.980 0.756 ;
      RECT 0.054 0.828 127.980 0.852 ;
      RECT 0.054 0.924 127.980 0.948 ;
      RECT 0.054 1.020 127.980 1.044 ;
      RECT 0.054 1.116 127.980 1.140 ;
      RECT 0.054 1.212 127.980 1.236 ;
      RECT 0.054 1.308 127.980 1.332 ;
      RECT 0.054 1.404 127.980 1.428 ;
      RECT 0.054 1.500 127.980 1.524 ;
      RECT 0.054 1.596 127.980 1.620 ;
      RECT 0.054 1.692 127.980 1.716 ;
      RECT 0.054 1.788 127.980 1.812 ;
      RECT 0.054 1.884 127.980 1.908 ;
      RECT 0.054 1.980 127.980 2.004 ;
      RECT 0.054 2.076 127.980 2.100 ;
      RECT 0.054 2.172 127.980 2.196 ;
      RECT 0.054 2.268 127.980 2.292 ;
      RECT 0.054 2.364 127.980 2.388 ;
      RECT 0.054 2.460 127.980 2.484 ;
      RECT 0.054 2.556 127.980 2.580 ;
      RECT 0.054 2.652 127.980 2.676 ;
      RECT 0.054 2.748 127.980 2.772 ;
      RECT 0.054 2.844 127.980 2.868 ;
      RECT 0.054 2.940 127.980 2.964 ;
      RECT 0.054 3.036 127.980 3.060 ;
      RECT 0.054 3.132 127.980 3.156 ;
      RECT 0.054 3.228 127.980 3.252 ;
      RECT 0.054 3.324 127.980 3.348 ;
      RECT 0.054 3.420 127.980 3.444 ;
      RECT 0.054 3.516 127.980 3.540 ;
      RECT 0.054 3.612 127.980 3.636 ;
      RECT 0.054 3.708 127.980 3.732 ;
      RECT 0.054 3.804 127.980 3.828 ;
      RECT 0.054 3.900 127.980 3.924 ;
      RECT 0.054 3.996 127.980 4.020 ;
      RECT 0.054 4.092 127.980 4.116 ;
      RECT 0.054 4.188 127.980 4.212 ;
      RECT 0.054 4.284 127.980 4.308 ;
      RECT 0.054 4.380 127.980 4.404 ;
      RECT 0.054 4.476 127.980 4.500 ;
      RECT 0.054 4.572 127.980 4.596 ;
      RECT 0.054 4.668 127.980 4.692 ;
      RECT 0.054 4.764 127.980 4.788 ;
      RECT 0.054 4.860 127.980 4.884 ;
      RECT 0.054 4.956 127.980 4.980 ;
      RECT 0.054 5.052 127.980 5.076 ;
      RECT 0.054 5.148 127.980 5.172 ;
      RECT 0.054 5.244 127.980 5.268 ;
      RECT 0.054 5.340 127.980 5.364 ;
      RECT 0.054 5.436 127.980 5.460 ;
      RECT 0.054 5.532 127.980 5.556 ;
      RECT 0.054 5.628 127.980 5.652 ;
      RECT 0.054 5.724 127.980 5.748 ;
      RECT 0.054 5.820 127.980 5.844 ;
      RECT 0.054 5.916 127.980 5.940 ;
      RECT 0.054 6.012 127.980 6.036 ;
      RECT 0.054 6.108 127.980 6.132 ;
      RECT 0.054 6.204 127.980 6.228 ;
      RECT 0.054 6.300 127.980 6.324 ;
      RECT 0.054 6.396 127.980 6.420 ;
      RECT 0.054 6.492 127.980 6.516 ;
      RECT 0.054 6.588 127.980 6.612 ;
      RECT 0.054 6.684 127.980 6.708 ;
      RECT 0.054 6.780 127.980 6.804 ;
      RECT 0.054 6.876 127.980 6.900 ;
      RECT 0.054 6.972 127.980 6.996 ;
      RECT 0.054 7.068 127.980 7.092 ;
      RECT 0.054 7.164 127.980 7.188 ;
      RECT 0.054 7.260 127.980 7.284 ;
      RECT 0.054 7.356 127.980 7.380 ;
      RECT 0.054 7.452 127.980 7.476 ;
      RECT 0.054 7.548 127.980 7.572 ;
      RECT 0.054 7.644 127.980 7.668 ;
      RECT 0.054 7.740 127.980 7.764 ;
      RECT 0.054 7.836 127.980 7.860 ;
      RECT 0.054 7.932 127.980 7.956 ;
      RECT 0.054 8.028 127.980 8.052 ;
      RECT 0.054 8.124 127.980 8.148 ;
      RECT 0.054 8.220 127.980 8.244 ;
      RECT 0.054 8.316 127.980 8.340 ;
      RECT 0.054 8.412 127.980 8.436 ;
      RECT 0.054 8.508 127.980 8.532 ;
      RECT 0.054 8.604 127.980 8.628 ;
      RECT 0.054 8.700 127.980 8.724 ;
      RECT 0.054 8.796 127.980 8.820 ;
      RECT 0.054 8.892 127.980 8.916 ;
      RECT 0.054 8.988 127.980 9.012 ;
      RECT 0.054 9.084 127.980 9.108 ;
      RECT 0.054 9.180 127.980 9.204 ;
      RECT 0.054 9.276 127.980 9.300 ;
      RECT 0.054 9.372 127.980 9.396 ;
      RECT 0.054 9.468 127.980 9.492 ;
      RECT 0.054 9.564 127.980 9.588 ;
      RECT 0.054 9.660 127.980 9.684 ;
      RECT 0.054 9.756 127.980 9.780 ;
      RECT 0.054 9.852 127.980 9.876 ;
      RECT 0.054 9.948 127.980 9.972 ;
      RECT 0.054 10.044 127.980 10.068 ;
      RECT 0.054 10.140 127.980 10.164 ;
      RECT 0.054 10.236 127.980 10.260 ;
      RECT 0.054 10.332 127.980 10.356 ;
      RECT 0.054 10.428 127.980 10.452 ;
      RECT 0.054 10.524 127.980 10.548 ;
      RECT 0.054 10.620 127.980 10.644 ;
      RECT 0.054 10.716 127.980 10.740 ;
      RECT 0.054 10.812 127.980 10.836 ;
      RECT 0.054 10.908 127.980 10.932 ;
      RECT 0.054 11.004 127.980 11.028 ;
      RECT 0.054 11.100 127.980 11.124 ;
      RECT 0.054 11.196 127.980 11.220 ;
      RECT 0.054 11.292 127.980 11.316 ;
      RECT 0.054 11.388 127.980 11.412 ;
      RECT 0.054 11.484 127.980 11.508 ;
      RECT 0.054 11.580 127.980 11.604 ;
      RECT 0.054 11.676 127.980 11.700 ;
      RECT 0.054 11.772 127.980 11.796 ;
      RECT 0.054 11.868 127.980 11.892 ;
      RECT 0.054 11.964 127.980 11.988 ;
      RECT 0.054 12.060 127.980 12.084 ;
      RECT 0.054 12.156 127.980 12.180 ;
      RECT 0.054 12.252 127.980 12.276 ;
      RECT 0.054 12.348 127.980 12.372 ;
      RECT 0.054 12.444 127.980 12.468 ;
      RECT 0.054 12.540 127.980 12.564 ;
      RECT 0.054 12.636 127.980 12.660 ;
      RECT 0.054 12.732 127.980 12.756 ;
      RECT 0.054 12.828 127.980 12.852 ;
      RECT 0.054 12.924 127.980 12.948 ;
      RECT 0.054 13.020 127.980 13.044 ;
      RECT 0.054 13.116 127.980 13.140 ;
      RECT 0.054 13.212 127.980 13.236 ;
      RECT 0.054 13.308 127.980 13.332 ;
      RECT 0.054 13.404 127.980 13.428 ;
      RECT 0.054 13.500 127.980 13.524 ;
      RECT 0.054 13.596 127.980 13.620 ;
      RECT 0.054 13.692 127.980 13.716 ;
      RECT 0.054 13.788 127.980 13.812 ;
      RECT 0.054 13.884 127.980 13.908 ;
      RECT 0.054 13.980 127.980 14.004 ;
      RECT 0.054 14.076 127.980 14.100 ;
      RECT 0.054 14.172 127.980 14.196 ;
      RECT 0.054 14.268 127.980 14.292 ;
      RECT 0.054 14.364 127.980 14.388 ;
      RECT 0.054 14.460 127.980 14.484 ;
      RECT 0.054 14.556 127.980 14.580 ;
      RECT 0.054 14.652 127.980 14.676 ;
      RECT 0.054 14.748 127.980 14.772 ;
      RECT 0.054 14.844 127.980 14.868 ;
      RECT 0.054 14.940 127.980 14.964 ;
      RECT 0.054 15.036 127.980 15.060 ;
      RECT 0.054 15.132 127.980 15.156 ;
      RECT 0.054 15.228 127.980 15.252 ;
      RECT 0.054 15.324 127.980 15.348 ;
      RECT 0.054 15.420 127.980 15.444 ;
      RECT 0.054 15.516 127.980 15.540 ;
      RECT 0.054 15.612 127.980 15.636 ;
      RECT 0.054 15.708 127.980 15.732 ;
      RECT 0.054 15.804 127.980 15.828 ;
      RECT 0.054 15.900 127.980 15.924 ;
      RECT 0.054 15.996 127.980 16.020 ;
      RECT 0.054 16.092 127.980 16.116 ;
      RECT 0.054 16.188 127.980 16.212 ;
      RECT 0.054 16.284 127.980 16.308 ;
      RECT 0.054 16.380 127.980 16.404 ;
      RECT 0.054 16.476 127.980 16.500 ;
      RECT 0.054 16.572 127.980 16.596 ;
      RECT 0.054 16.668 127.980 16.692 ;
      RECT 0.054 16.764 127.980 16.788 ;
      RECT 0.054 16.860 127.980 16.884 ;
      RECT 0.054 16.956 127.980 16.980 ;
      RECT 0.054 17.052 127.980 17.076 ;
      RECT 0.054 17.148 127.980 17.172 ;
      RECT 0.054 17.244 127.980 17.268 ;
      RECT 0.054 17.340 127.980 17.364 ;
      RECT 0.054 17.436 127.980 17.460 ;
      RECT 0.054 17.532 127.980 17.556 ;
      RECT 0.054 17.628 127.980 17.652 ;
      RECT 0.054 17.724 127.980 17.748 ;
      RECT 0.054 17.820 127.980 17.844 ;
      RECT 0.054 17.916 127.980 17.940 ;
      RECT 0.054 18.012 127.980 18.036 ;
      RECT 0.054 18.108 127.980 18.132 ;
      RECT 0.054 18.204 127.980 18.228 ;
      RECT 0.054 18.300 127.980 18.324 ;
      RECT 0.054 18.396 127.980 18.420 ;
      RECT 0.054 18.492 127.980 18.516 ;
      RECT 0.054 18.588 127.980 18.612 ;
      RECT 0.054 18.684 127.980 18.708 ;
      RECT 0.054 18.780 127.980 18.804 ;
      RECT 0.054 18.876 127.980 18.900 ;
      RECT 0.054 18.972 127.980 18.996 ;
      RECT 0.054 19.068 127.980 19.092 ;
      RECT 0.054 19.164 127.980 19.188 ;
      RECT 0.054 19.260 127.980 19.284 ;
      RECT 0.054 19.356 127.980 19.380 ;
      RECT 0.054 19.452 127.980 19.476 ;
      RECT 0.054 19.548 127.980 19.572 ;
      RECT 0.054 19.644 127.980 19.668 ;
      RECT 0.054 19.740 127.980 19.764 ;
      RECT 0.054 19.836 127.980 19.860 ;
      RECT 0.054 19.932 127.980 19.956 ;
      RECT 0.054 20.028 127.980 20.052 ;
      RECT 0.054 20.124 127.980 20.148 ;
      RECT 0.054 20.220 127.980 20.244 ;
      RECT 0.054 20.316 127.980 20.340 ;
      RECT 0.054 20.412 127.980 20.436 ;
      RECT 0.054 20.508 127.980 20.532 ;
      RECT 0.054 20.604 127.980 20.628 ;
      RECT 0.054 20.700 127.980 20.724 ;
      RECT 0.054 20.796 127.980 20.820 ;
      RECT 0.054 20.892 127.980 20.916 ;
      RECT 0.054 20.988 127.980 21.012 ;
      RECT 0.054 21.084 127.980 21.108 ;
      RECT 0.054 21.180 127.980 21.204 ;
      RECT 0.054 21.276 127.980 21.300 ;
      RECT 0.054 21.372 127.980 21.396 ;
      RECT 0.054 21.468 127.980 21.492 ;
      RECT 0.054 21.564 127.980 21.588 ;
      RECT 0.054 21.660 127.980 21.684 ;
      RECT 0.054 21.756 127.980 21.780 ;
      RECT 0.054 21.852 127.980 21.876 ;
      RECT 0.054 21.948 127.980 21.972 ;
      RECT 0.054 22.044 127.980 22.068 ;
      RECT 0.054 22.140 127.980 22.164 ;
      RECT 0.054 22.236 127.980 22.260 ;
      RECT 0.054 22.332 127.980 22.356 ;
      RECT 0.054 22.428 127.980 22.452 ;
      RECT 0.054 22.524 127.980 22.548 ;
      RECT 0.054 22.620 127.980 22.644 ;
      RECT 0.054 22.716 127.980 22.740 ;
      RECT 0.054 22.812 127.980 22.836 ;
      RECT 0.054 22.908 127.980 22.932 ;
      RECT 0.054 23.004 127.980 23.028 ;
      RECT 0.054 23.100 127.980 23.124 ;
      RECT 0.054 23.196 127.980 23.220 ;
      RECT 0.054 23.292 127.980 23.316 ;
      RECT 0.054 23.388 127.980 23.412 ;
      RECT 0.054 23.484 127.980 23.508 ;
      RECT 0.054 23.580 127.980 23.604 ;
      RECT 0.054 23.676 127.980 23.700 ;
      RECT 0.054 23.772 127.980 23.796 ;
      RECT 0.054 23.868 127.980 23.892 ;
      RECT 0.054 23.964 127.980 23.988 ;
      RECT 0.054 24.060 127.980 24.084 ;
      RECT 0.054 24.156 127.980 24.180 ;
      RECT 0.054 24.252 127.980 24.276 ;
      RECT 0.054 24.348 127.980 24.372 ;
      RECT 0.054 24.444 127.980 24.468 ;
      RECT 0.054 24.540 127.980 24.564 ;
      RECT 0.054 24.636 127.980 24.660 ;
      RECT 0.054 24.732 127.980 24.756 ;
      RECT 0.054 24.828 127.980 24.852 ;
      RECT 0.054 24.924 127.980 24.948 ;
      RECT 0.054 25.020 127.980 25.044 ;
      RECT 0.054 25.116 127.980 25.140 ;
      RECT 0.054 25.212 127.980 25.236 ;
      RECT 0.054 25.308 127.980 25.332 ;
      RECT 0.054 25.404 127.980 25.428 ;
      RECT 0.054 25.500 127.980 25.524 ;
      RECT 0.054 25.596 127.980 25.620 ;
      RECT 0.054 25.692 127.980 25.716 ;
      RECT 0.054 25.788 127.980 25.812 ;
      RECT 0.054 25.884 127.980 25.908 ;
      RECT 0.054 25.980 127.980 26.004 ;
      RECT 0.054 26.076 127.980 26.100 ;
      RECT 0.054 26.172 127.980 26.196 ;
      RECT 0.054 26.268 127.980 26.292 ;
      RECT 0.054 26.364 127.980 26.388 ;
      RECT 0.054 26.460 127.980 26.484 ;
      RECT 0.054 26.556 127.980 26.580 ;
      RECT 0.054 26.652 127.980 26.676 ;
      RECT 0.054 26.748 127.980 26.772 ;
      RECT 0.054 26.844 127.980 26.868 ;
      RECT 0.054 26.940 127.980 26.964 ;
      RECT 0.054 27.036 127.980 27.060 ;
      RECT 0.054 27.132 127.980 27.156 ;
      RECT 0.054 27.228 127.980 27.252 ;
      RECT 0.054 27.324 127.980 27.348 ;
      RECT 0.054 27.420 127.980 27.444 ;
      RECT 0.054 27.516 127.980 27.540 ;
      RECT 0.054 27.612 127.980 27.636 ;
      RECT 0.054 27.708 127.980 27.732 ;
      RECT 0.054 27.804 127.980 27.828 ;
      RECT 0.054 27.900 127.980 27.924 ;
      RECT 0.054 27.996 127.980 28.020 ;
      RECT 0.054 28.092 127.980 28.116 ;
      RECT 0.054 28.188 127.980 28.212 ;
      RECT 0.054 28.284 127.980 28.308 ;
      RECT 0.054 28.380 127.980 28.404 ;
      RECT 0.054 28.476 127.980 28.500 ;
      RECT 0.054 28.572 127.980 28.596 ;
      RECT 0.054 28.668 127.980 28.692 ;
      RECT 0.054 28.764 127.980 28.788 ;
      RECT 0.054 28.860 127.980 28.884 ;
      RECT 0.054 28.956 127.980 28.980 ;
      RECT 0.054 29.052 127.980 29.076 ;
      RECT 0.054 29.148 127.980 29.172 ;
      RECT 0.054 29.244 127.980 29.268 ;
      RECT 0.054 29.340 127.980 29.364 ;
      RECT 0.054 29.436 127.980 29.460 ;
      RECT 0.054 29.532 127.980 29.556 ;
      RECT 0.054 29.628 127.980 29.652 ;
      RECT 0.054 29.724 127.980 29.748 ;
      RECT 0.054 29.820 127.980 29.844 ;
      RECT 0.054 29.916 127.980 29.940 ;
      RECT 0.054 30.012 127.980 30.036 ;
      RECT 0.054 30.108 127.980 30.132 ;
      RECT 0.054 30.204 127.980 30.228 ;
      RECT 0.054 30.300 127.980 30.324 ;
      RECT 0.054 30.396 127.980 30.420 ;
      RECT 0.054 30.492 127.980 30.516 ;
      RECT 0.054 30.588 127.980 30.612 ;
      RECT 0.054 30.684 127.980 30.708 ;
      RECT 0.054 30.780 127.980 30.804 ;
      RECT 0.054 30.876 127.980 30.900 ;
      RECT 0.054 30.972 127.980 30.996 ;
      RECT 0.054 31.068 127.980 31.092 ;
      RECT 0.054 31.164 127.980 31.188 ;
      RECT 0.054 31.260 127.980 31.284 ;
      RECT 0.054 31.356 127.980 31.380 ;
      RECT 0.054 31.452 127.980 31.476 ;
      RECT 0.054 31.548 127.980 31.572 ;
      RECT 0.054 31.644 127.980 31.668 ;
      RECT 0.054 31.740 127.980 31.764 ;
      RECT 0.054 31.836 127.980 31.860 ;
      RECT 0.054 31.932 127.980 31.956 ;
      RECT 0.054 32.028 127.980 32.052 ;
      RECT 0.054 32.124 127.980 32.148 ;
      RECT 0.054 32.220 127.980 32.244 ;
      RECT 0.054 32.316 127.980 32.340 ;
      RECT 0.054 32.412 127.980 32.436 ;
      RECT 0.054 32.508 127.980 32.532 ;
      RECT 0.054 32.604 127.980 32.628 ;
      RECT 0.054 32.700 127.980 32.724 ;
      RECT 0.054 32.796 127.980 32.820 ;
      RECT 0.054 32.892 127.980 32.916 ;
      RECT 0.054 32.988 127.980 33.012 ;
      RECT 0.054 33.084 127.980 33.108 ;
      RECT 0.054 33.180 127.980 33.204 ;
      RECT 0.054 33.276 127.980 33.300 ;
      RECT 0.054 33.372 127.980 33.396 ;
      RECT 0.054 33.468 127.980 33.492 ;
      RECT 0.054 33.564 127.980 33.588 ;
      RECT 0.054 33.660 127.980 33.684 ;
      RECT 0.054 33.756 127.980 33.780 ;
      RECT 0.054 33.852 127.980 33.876 ;
      RECT 0.054 33.948 127.980 33.972 ;
      RECT 0.054 34.044 127.980 34.068 ;
      RECT 0.054 34.140 127.980 34.164 ;
      RECT 0.054 34.236 127.980 34.260 ;
      RECT 0.054 34.332 127.980 34.356 ;
      RECT 0.054 34.428 127.980 34.452 ;
      RECT 0.054 34.524 127.980 34.548 ;
      RECT 0.054 34.620 127.980 34.644 ;
      RECT 0.054 34.716 127.980 34.740 ;
      RECT 0.054 34.812 127.980 34.836 ;
      RECT 0.054 34.908 127.980 34.932 ;
      RECT 0.054 35.004 127.980 35.028 ;
      RECT 0.054 35.100 127.980 35.124 ;
      RECT 0.054 35.196 127.980 35.220 ;
      RECT 0.054 35.292 127.980 35.316 ;
      RECT 0.054 35.388 127.980 35.412 ;
      RECT 0.054 35.484 127.980 35.508 ;
      RECT 0.054 35.580 127.980 35.604 ;
      RECT 0.054 35.676 127.980 35.700 ;
      RECT 0.054 35.772 127.980 35.796 ;
      RECT 0.054 35.868 127.980 35.892 ;
      RECT 0.054 35.964 127.980 35.988 ;
      RECT 0.054 36.060 127.980 36.084 ;
      RECT 0.054 36.156 127.980 36.180 ;
      RECT 0.054 36.252 127.980 36.276 ;
      RECT 0.054 36.348 127.980 36.372 ;
      RECT 0.054 36.444 127.980 36.468 ;
      RECT 0.054 36.540 127.980 36.564 ;
      RECT 0.054 36.636 127.980 36.660 ;
      RECT 0.054 36.732 127.980 36.756 ;
      RECT 0.054 36.828 127.980 36.852 ;
      RECT 0.054 36.924 127.980 36.948 ;
      RECT 0.054 37.020 127.980 37.044 ;
      RECT 0.054 37.116 127.980 37.140 ;
      RECT 0.054 37.212 127.980 37.236 ;
      RECT 0.054 37.308 127.980 37.332 ;
      RECT 0.054 37.404 127.980 37.428 ;
      RECT 0.054 37.500 127.980 37.524 ;
      RECT 0.054 37.596 127.980 37.620 ;
      RECT 0.054 37.692 127.980 37.716 ;
      RECT 0.054 37.788 127.980 37.812 ;
      RECT 0.054 37.884 127.980 37.908 ;
      RECT 0.054 37.980 127.980 38.004 ;
      RECT 0.054 38.076 127.980 38.100 ;
      RECT 0.054 38.172 127.980 38.196 ;
      RECT 0.054 38.268 127.980 38.292 ;
      RECT 0.054 38.364 127.980 38.388 ;
      RECT 0.054 38.460 127.980 38.484 ;
      RECT 0.054 38.556 127.980 38.580 ;
      RECT 0.054 38.652 127.980 38.676 ;
      RECT 0.054 38.748 127.980 38.772 ;
      RECT 0.054 38.844 127.980 38.868 ;
      RECT 0.054 38.940 127.980 38.964 ;
      RECT 0.054 39.036 127.980 39.060 ;
      RECT 0.054 39.132 127.980 39.156 ;
      RECT 0.054 39.228 127.980 39.252 ;
      RECT 0.054 39.324 127.980 39.348 ;
      RECT 0.054 39.420 127.980 39.444 ;
      RECT 0.054 39.516 127.980 39.540 ;
      RECT 0.054 39.612 127.980 39.636 ;
      RECT 0.054 39.708 127.980 39.732 ;
      RECT 0.054 39.804 127.980 39.828 ;
      RECT 0.054 39.900 127.980 39.924 ;
      RECT 0.054 39.996 127.980 40.020 ;
      RECT 0.054 40.092 127.980 40.116 ;
      RECT 0.054 40.188 127.980 40.212 ;
      RECT 0.054 40.284 127.980 40.308 ;
      RECT 0.054 40.380 127.980 40.404 ;
      RECT 0.054 40.476 127.980 40.500 ;
      RECT 0.054 40.572 127.980 40.596 ;
      RECT 0.054 40.668 127.980 40.692 ;
      RECT 0.054 40.764 127.980 40.788 ;
      RECT 0.054 40.860 127.980 40.884 ;
      RECT 0.054 40.956 127.980 40.980 ;
      RECT 0.054 41.052 127.980 41.076 ;
      RECT 0.054 41.148 127.980 41.172 ;
      RECT 0.054 41.244 127.980 41.268 ;
      RECT 0.054 41.340 127.980 41.364 ;
      RECT 0.054 41.436 127.980 41.460 ;
      RECT 0.054 41.532 127.980 41.556 ;
      RECT 0.054 41.628 127.980 41.652 ;
      RECT 0.054 41.724 127.980 41.748 ;
      RECT 0.054 41.820 127.980 41.844 ;
      RECT 0.054 41.916 127.980 41.940 ;
      RECT 0.054 42.012 127.980 42.036 ;
      RECT 0.054 42.108 127.980 42.132 ;
      RECT 0.054 42.204 127.980 42.228 ;
      RECT 0.054 42.300 127.980 42.324 ;
      RECT 0.054 42.396 127.980 42.420 ;
      RECT 0.054 42.492 127.980 42.516 ;
      RECT 0.054 42.588 127.980 42.612 ;
      RECT 0.054 42.684 127.980 42.708 ;
      RECT 0.054 42.780 127.980 42.804 ;
      RECT 0.054 42.876 127.980 42.900 ;
      RECT 0.054 42.972 127.980 42.996 ;
      RECT 0.054 43.068 127.980 43.092 ;
      RECT 0.054 43.164 127.980 43.188 ;
      RECT 0.054 43.260 127.980 43.284 ;
      RECT 0.054 43.356 127.980 43.380 ;
      RECT 0.054 43.452 127.980 43.476 ;
      RECT 0.054 43.548 127.980 43.572 ;
      RECT 0.054 43.644 127.980 43.668 ;
      RECT 0.054 43.740 127.980 43.764 ;
      RECT 0.054 43.836 127.980 43.860 ;
      RECT 0.054 43.932 127.980 43.956 ;
      RECT 0.054 44.028 127.980 44.052 ;
      RECT 0.054 44.124 127.980 44.148 ;
      RECT 0.054 44.220 127.980 44.244 ;
      RECT 0.054 44.316 127.980 44.340 ;
      RECT 0.054 44.412 127.980 44.436 ;
      RECT 0.054 44.508 127.980 44.532 ;
      RECT 0.054 44.604 127.980 44.628 ;
      RECT 0.054 44.700 127.980 44.724 ;
      RECT 0.054 44.796 127.980 44.820 ;
      RECT 0.054 44.892 127.980 44.916 ;
      RECT 0.054 44.988 127.980 45.012 ;
      RECT 0.054 45.084 127.980 45.108 ;
      RECT 0.054 45.180 127.980 45.204 ;
      RECT 0.054 45.276 127.980 45.300 ;
      RECT 0.054 45.372 127.980 45.396 ;
      RECT 0.054 45.468 127.980 45.492 ;
      RECT 0.054 45.564 127.980 45.588 ;
      RECT 0.054 45.660 127.980 45.684 ;
      RECT 0.054 45.756 127.980 45.780 ;
      RECT 0.054 45.852 127.980 45.876 ;
      RECT 0.054 45.948 127.980 45.972 ;
      RECT 0.054 46.044 127.980 46.068 ;
      RECT 0.054 46.140 127.980 46.164 ;
      RECT 0.054 46.236 127.980 46.260 ;
      RECT 0.054 46.332 127.980 46.356 ;
      RECT 0.054 46.428 127.980 46.452 ;
      RECT 0.054 46.524 127.980 46.548 ;
      RECT 0.054 46.620 127.980 46.644 ;
      RECT 0.054 46.716 127.980 46.740 ;
      RECT 0.054 46.812 127.980 46.836 ;
      RECT 0.054 46.908 127.980 46.932 ;
      RECT 0.054 47.004 127.980 47.028 ;
      RECT 0.054 47.100 127.980 47.124 ;
      RECT 0.054 47.196 127.980 47.220 ;
      RECT 0.054 47.292 127.980 47.316 ;
      RECT 0.054 47.388 127.980 47.412 ;
      RECT 0.054 47.484 127.980 47.508 ;
      RECT 0.054 47.580 127.980 47.604 ;
      RECT 0.054 47.676 127.980 47.700 ;
      RECT 0.054 47.772 127.980 47.796 ;
      RECT 0.054 47.868 127.980 47.892 ;
      RECT 0.054 47.964 127.980 47.988 ;
      RECT 0.054 48.060 127.980 48.084 ;
      RECT 0.054 48.156 127.980 48.180 ;
      RECT 0.054 48.252 127.980 48.276 ;
      RECT 0.054 48.348 127.980 48.372 ;
      RECT 0.054 48.444 127.980 48.468 ;
      RECT 0.054 48.540 127.980 48.564 ;
      RECT 0.054 48.636 127.980 48.660 ;
      RECT 0.054 48.732 127.980 48.756 ;
      RECT 0.054 48.828 127.980 48.852 ;
      RECT 0.054 48.924 127.980 48.948 ;
      RECT 0.054 49.020 127.980 49.044 ;
      RECT 0.054 49.116 127.980 49.140 ;
      RECT 0.054 49.212 127.980 49.236 ;
      RECT 0.054 49.308 127.980 49.332 ;
      RECT 0.054 49.404 127.980 49.428 ;
      RECT 0.054 49.500 127.980 49.524 ;
      RECT 0.054 49.596 127.980 49.620 ;
      RECT 0.054 49.692 127.980 49.716 ;
      RECT 0.054 49.788 127.980 49.812 ;
      RECT 0.054 49.884 127.980 49.908 ;
      RECT 0.054 49.980 127.980 50.004 ;
      RECT 0.054 50.076 127.980 50.100 ;
      RECT 0.054 50.172 127.980 50.196 ;
      RECT 0.054 50.268 127.980 50.292 ;
      RECT 0.054 50.364 127.980 50.388 ;
      RECT 0.054 50.460 127.980 50.484 ;
      RECT 0.054 50.556 127.980 50.580 ;
      RECT 0.054 50.652 127.980 50.676 ;
      RECT 0.054 50.748 127.980 50.772 ;
      RECT 0.054 50.844 127.980 50.868 ;
      RECT 0.054 50.940 127.980 50.964 ;
      RECT 0.054 51.036 127.980 51.060 ;
      RECT 0.054 51.132 127.980 51.156 ;
      RECT 0.054 51.228 127.980 51.252 ;
      RECT 0.054 51.324 127.980 51.348 ;
      RECT 0.054 51.420 127.980 51.444 ;
      RECT 0.054 51.516 127.980 51.540 ;
      RECT 0.054 51.612 127.980 51.636 ;
      RECT 0.054 51.708 127.980 51.732 ;
      RECT 0.054 51.804 127.980 51.828 ;
      RECT 0.054 51.900 127.980 51.924 ;
      RECT 0.054 51.996 127.980 52.020 ;
      RECT 0.054 52.092 127.980 52.116 ;
      RECT 0.054 52.188 127.980 52.212 ;
      RECT 0.054 52.284 127.980 52.308 ;
      RECT 0.054 52.380 127.980 52.404 ;
      RECT 0.054 52.476 127.980 52.500 ;
      RECT 0.054 52.572 127.980 52.596 ;
      RECT 0.054 52.668 127.980 52.692 ;
      RECT 0.054 52.764 127.980 52.788 ;
      RECT 0.054 52.860 127.980 52.884 ;
      RECT 0.054 52.956 127.980 52.980 ;
      RECT 0.054 53.052 127.980 53.076 ;
      RECT 0.054 53.148 127.980 53.172 ;
      RECT 0.054 53.244 127.980 53.268 ;
      RECT 0.054 53.340 127.980 53.364 ;
      RECT 0.054 53.436 127.980 53.460 ;
      RECT 0.054 53.532 127.980 53.556 ;
      RECT 0.054 53.628 127.980 53.652 ;
      RECT 0.054 53.724 127.980 53.748 ;
      RECT 0.054 53.820 127.980 53.844 ;
      RECT 0.054 53.916 127.980 53.940 ;
      RECT 0.054 54.012 127.980 54.036 ;
      RECT 0.054 54.108 127.980 54.132 ;
      RECT 0.054 54.204 127.980 54.228 ;
      RECT 0.054 54.300 127.980 54.324 ;
      RECT 0.054 54.396 127.980 54.420 ;
      RECT 0.054 54.492 127.980 54.516 ;
      RECT 0.054 54.588 127.980 54.612 ;
      RECT 0.054 54.684 127.980 54.708 ;
      RECT 0.054 54.780 127.980 54.804 ;
      RECT 0.054 54.876 127.980 54.900 ;
      RECT 0.054 54.972 127.980 54.996 ;
      RECT 0.054 55.068 127.980 55.092 ;
      RECT 0.054 55.164 127.980 55.188 ;
      RECT 0.054 55.260 127.980 55.284 ;
      RECT 0.054 55.356 127.980 55.380 ;
      RECT 0.054 55.452 127.980 55.476 ;
      RECT 0.054 55.548 127.980 55.572 ;
      RECT 0.054 55.644 127.980 55.668 ;
      RECT 0.054 55.740 127.980 55.764 ;
      RECT 0.054 55.836 127.980 55.860 ;
      RECT 0.054 55.932 127.980 55.956 ;
      RECT 0.054 56.028 127.980 56.052 ;
      RECT 0.054 56.124 127.980 56.148 ;
      RECT 0.054 56.220 127.980 56.244 ;
      RECT 0.054 56.316 127.980 56.340 ;
      RECT 0.054 56.412 127.980 56.436 ;
      RECT 0.054 56.508 127.980 56.532 ;
      RECT 0.054 56.604 127.980 56.628 ;
      RECT 0.054 56.700 127.980 56.724 ;
      RECT 0.054 56.796 127.980 56.820 ;
      RECT 0.054 56.892 127.980 56.916 ;
      RECT 0.054 56.988 127.980 57.012 ;
      RECT 0.054 57.084 127.980 57.108 ;
      RECT 0.054 57.180 127.980 57.204 ;
      RECT 0.054 57.276 127.980 57.300 ;
      RECT 0.054 57.372 127.980 57.396 ;
      RECT 0.054 57.468 127.980 57.492 ;
      RECT 0.054 57.564 127.980 57.588 ;
      RECT 0.054 57.660 127.980 57.684 ;
      RECT 0.054 57.756 127.980 57.780 ;
      RECT 0.054 57.852 127.980 57.876 ;
      RECT 0.054 57.948 127.980 57.972 ;
      RECT 0.054 58.044 127.980 58.068 ;
      RECT 0.054 58.140 127.980 58.164 ;
      RECT 0.054 58.236 127.980 58.260 ;
      RECT 0.054 58.332 127.980 58.356 ;
      RECT 0.054 58.428 127.980 58.452 ;
      RECT 0.054 58.524 127.980 58.548 ;
      RECT 0.054 58.620 127.980 58.644 ;
      RECT 0.054 58.716 127.980 58.740 ;
      RECT 0.054 58.812 127.980 58.836 ;
      RECT 0.054 58.908 127.980 58.932 ;
      RECT 0.054 59.004 127.980 59.028 ;
      RECT 0.054 59.100 127.980 59.124 ;
      RECT 0.054 59.196 127.980 59.220 ;
      RECT 0.054 59.292 127.980 59.316 ;
      RECT 0.054 59.388 127.980 59.412 ;
      RECT 0.054 59.484 127.980 59.508 ;
      RECT 0.054 59.580 127.980 59.604 ;
      RECT 0.054 59.676 127.980 59.700 ;
      RECT 0.054 59.772 127.980 59.796 ;
      RECT 0.054 59.868 127.980 59.892 ;
      RECT 0.054 59.964 127.980 59.988 ;
      RECT 0.054 60.060 127.980 60.084 ;
      RECT 0.054 60.156 127.980 60.180 ;
      RECT 0.054 60.252 127.980 60.276 ;
      RECT 0.054 60.348 127.980 60.372 ;
      RECT 0.054 60.444 127.980 60.468 ;
      RECT 0.054 60.540 127.980 60.564 ;
      RECT 0.054 60.636 127.980 60.660 ;
      RECT 0.054 60.732 127.980 60.756 ;
      RECT 0.054 60.828 127.980 60.852 ;
      RECT 0.054 60.924 127.980 60.948 ;
      RECT 0.054 61.020 127.980 61.044 ;
      RECT 0.054 61.116 127.980 61.140 ;
      RECT 0.054 61.212 127.980 61.236 ;
      RECT 0.054 61.308 127.980 61.332 ;
      RECT 0.054 61.404 127.980 61.428 ;
      RECT 0.054 61.500 127.980 61.524 ;
      RECT 0.054 61.596 127.980 61.620 ;
      RECT 0.054 61.692 127.980 61.716 ;
      RECT 0.054 61.788 127.980 61.812 ;
      RECT 0.054 61.884 127.980 61.908 ;
      RECT 0.054 61.980 127.980 62.004 ;
      RECT 0.054 62.076 127.980 62.100 ;
      RECT 0.054 62.172 127.980 62.196 ;
      RECT 0.054 62.268 127.980 62.292 ;
      RECT 0.054 62.364 127.980 62.388 ;
      RECT 0.054 62.460 127.980 62.484 ;
      RECT 0.054 62.556 127.980 62.580 ;
      RECT 0.054 62.652 127.980 62.676 ;
      RECT 0.054 62.748 127.980 62.772 ;
      RECT 0.054 62.844 127.980 62.868 ;
      RECT 0.054 62.940 127.980 62.964 ;
      RECT 0.054 63.036 127.980 63.060 ;
      RECT 0.054 63.132 127.980 63.156 ;
      RECT 0.054 63.228 127.980 63.252 ;
      RECT 0.054 63.324 127.980 63.348 ;
      RECT 0.054 63.420 127.980 63.444 ;
      RECT 0.054 63.516 127.980 63.540 ;
      RECT 0.054 63.612 127.980 63.636 ;
      RECT 0.054 63.708 127.980 63.732 ;
      RECT 0.054 63.804 127.980 63.828 ;
      RECT 0.054 63.900 127.980 63.924 ;
      RECT 0.054 63.996 127.980 64.020 ;
      RECT 0.054 64.092 127.980 64.116 ;
      RECT 0.054 64.188 127.980 64.212 ;
    END
  END VSS
  OBS
    LAYER M1 ;
      RECT 0.000 0.000 128.034 64.260 ;
    LAYER M2 ;
      RECT 0.000 0.000 128.034 64.260 ;
    LAYER M3 ;
      RECT 0.000 0.000 128.034 64.260 ;
  END
END fakeram7_1024x16
END LIBRARY
